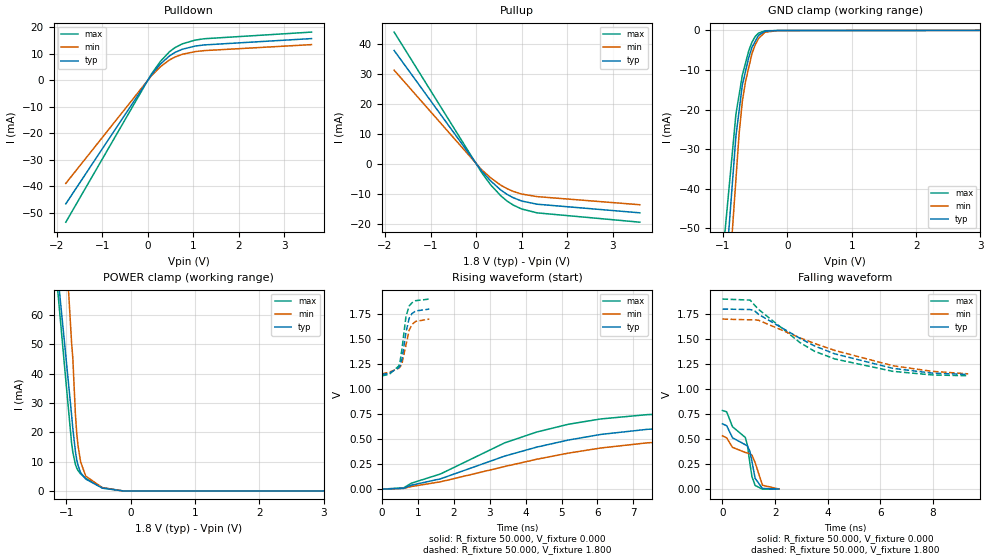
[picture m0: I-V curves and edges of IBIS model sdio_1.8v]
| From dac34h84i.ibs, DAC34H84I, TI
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[Model]   sdio_1.8v
Model_type I/O
Vinl=5.400E-01
Vinh=1.260E+00
Vref=0.000E+00
Rref=1.000E+06
Cref=0.000E+00
Vmeas=9.000E-01
C_comp   6.740E-13   6.530E-13   6.950E-13
[Voltage Range]   1.800E+00   1.700E+00   1.900E+00
[POWER Clamp Reference]   1.800E+00   1.700E+00   1.900E+00
[GND Clamp Reference]   0.000E+00   0.000E+00   0.000E+00
[Pullup Reference]   1.800E+00   1.700E+00   1.900E+00
[Pulldown Reference]   0.000E+00   0.000E+00   0.000E+00
[Temperature Range] 25   125   -40
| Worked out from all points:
|   slope of the pulldown table from 0 to 0.27 V, typ, clamps not added: 45.6 ohm
|   slope of the pullup table from 0 to 0.27 V, typ, clamps not added: 54.8 ohm
|   GND clamp passes 1 mA (typ) near -0.43 V on its own axis
|   POWER clamp passes 1 mA (typ) near -0.45 V on its own axis
|   rising waveform, R_fixture 50.000, V_fixture 0.000: 20-80 % time 3.77ns typ, 4.29ns min, 3.27ns max; typ from 0 V to 0.652 V
|   falling waveform, R_fixture 50.000, V_fixture 0.000: 20-80 % time 870ps typ, 1.05ns min, 732ps max; typ from 0.652 V to 0 V
|   rising waveform, R_fixture 50.000, V_fixture 1.800: 20-80 % time 181ps typ, 197ps min, 170ps max; typ from 1.15 V to 1.8 V
|   falling waveform, R_fixture 50.000, V_fixture 1.800: 20-80 % time 3.42ns typ, 3.84ns min, 2.82ns max; typ from 1.8 V to 1.15 V
[GND Clamp]
-1.8V     -242.4mA   -269.9mA   -195.7mA
-800mV    -26.7mA    -37.63mA   -21.15mA
-750mV    -20.22mA   -26.01mA   -16.21mA
-700mV    -13.73mA   -17.89mA   -11.26mA
-650mV    -10.26mA   -12.81mA   -8.173mA
-600mV    -6.781mA   -9.304mA   -5.08mA
-550mV    -4.257mA   -5.802mA   -2.937mA
-500mV    -2.753mA   -3.618mA   -1.517mA
-450mV    -1.249mA   -2.055mA   -667.8uA
-350mV    -200.6uA   -456.3uA   -72.45uA
-150mV    -15.42uA   -17.32uA   -17.32uA
3.6V      32.18uA    37.62uA    21.08uA
[Power Clamp]
-1.8V     222mA      379.6mA    231.2mA
-1.02V    48.49mA    88.18mA    40.38mA
-920mV    26.11mA    50.82mA    16.48mA
-900mV    21.28mA    45.26mA    13.24mA
-860mV    13.47mA    26.21mA    9.068mA
-840mV    10.76mA    19.8mA     7.859mA
-820mV    8.766mA    15.59mA    6.999mA
-780mV    6.293mA    10.03mA    5.834mA
-700mV    4.052mA    5.069mA    4.276mA
-440mV    932.9uA    1.089mA    1.116mA
-120mV    0A         0A         0A
3.6V      0A         0A         0A
[Pullup]
-1.8V     37.98mA    31.37mA    44.14mA
120mV     -2.343mA   -1.92mA    -2.846mA
320mV     -5.701mA   -4.66mA    -7.03mA
540mV     -8.745mA   -7.128mA   -10.64mA
680mV     -10.23mA   -8.304mA   -12.46mA
820mV     -11.37mA   -9.256mA   -13.84mA
1V        -12.45mA   -10.12mA   -15.12mA
1.34V     -13.53mA   -10.99mA   -16.43mA
3.6V      -16.42mA   -13.71mA   -19.56mA
[Pulldown]
-1.8V     -46.56mA   -38.86mA   -53.48mA
80mV      1.966mA    1.636mA    2.274mA
280mV     6.106mA    5.077mA    7.112mA
480mV     9.176mA    7.651mA    10.74mA
600mV     10.48mA    8.749mA    12.28mA
760mV     11.66mA    9.756mA    13.69mA
1.04V     12.85mA    10.77mA    15.1mA
1.24V     13.29mA    11.15mA    15.62mA
3.6V      15.68mA    13.41mA    18.13mA
[Rising Waveform]
R_fixture = 50.000
V_fixture = 0.000
V_fixture_min = 0.000
V_fixture_max = 0.000
|  time   V(typ)   V(min)   V(max)
0s        303.1uV    373.8uV    325.9uV
610ps     8.633mV    8.615mV    14.26mV
820ps     40.04mV    26.87mV    59.82mV
1.63ns    103.3mV    73.66mV    152mV
3.42ns    331.1mV    226.8mV    463.4mV
4.31ns    420.5mV    299.3mV    571.3mV
5.19ns    491.1mV    360.4mV    648.9mV
6.09ns    547.1mV    411.6mV    702mV
7.39ns    598.5mV    463.5mV    745.3mV
11.14ns   651.9mV    532mV      785.2mV
[Falling Waveform]
R_fixture = 50.000
V_fixture = 0.000
V_fixture_min = 0.000
V_fixture_max = 0.000
|  time   V(typ)   V(min)   V(max)
0s        651.9mV    532mV      785.2mV
160ps     633mV      511.5mV    772.3mV
380ps     512.6mV    417mV      623.1mV
870ps     442.9mV    365.5mV    515.6mV
950ps     429.7mV    360.1mV    434.3mV
1.04ns    378.4mV    353.9mV    262.4mV
1.12ns    275.9mV    339.1mV    124.9mV
1.24ns    107.1mV    265.1mV    36.24mV
1.52ns    5.53mV     38.13mV    -1.427mV
2.14ns    303.1uV    373.8uV    325.9uV
[Rising Waveform]
R_fixture = 50.000
V_fixture = 1.800
V_fixture_min = 1.700
V_fixture_max = 1.900
|  time   V(typ)   V(min)   V(max)
0s        1.146V     1.152V     1.133V
200ps     1.158V     1.169V     1.146V
470ps     1.214V     1.208V     1.231V
510ps     1.237V     1.222V     1.282V
560ps     1.301V     1.257V     1.403V
670ps     1.567V     1.439V     1.725V
760ps     1.709V     1.589V     1.831V
840ps     1.756V     1.647V     1.863V
940ps     1.781V     1.677V     1.884V
1.32ns    1.8V       1.7V       1.9V
[Falling Waveform]
R_fixture = 50.000
V_fixture = 1.800
V_fixture_min = 1.700
V_fixture_max = 1.900
|  time   V(typ)   V(min)   V(max)
0s        1.8V       1.7V       1.9V
1.05ns    1.795V     1.692V     1.89V
1.21ns    1.786V     1.693V     1.842V
1.37ns    1.747V     1.688V     1.797V
2.95ns    1.507V     1.512V     1.464V
3.5ns     1.431V     1.456V     1.378V
4.27ns    1.352V     1.386V     1.301V
6.48ns    1.207V     1.233V     1.177V
7.98ns    1.159V     1.177V     1.141V
9.34ns    1.146V     1.152V     1.133V
[Ramp]
dV/dt_r   3.9031E-01/3.7675E-09   3.1871E-01/4.2841E-09   4.6746E-01/3.2656E-09
dV/dt_f   3.9249E-01/3.4144E-09   3.2885E-01/3.8422E-09   4.5993E-01/2.8128E-09
R_load = 50
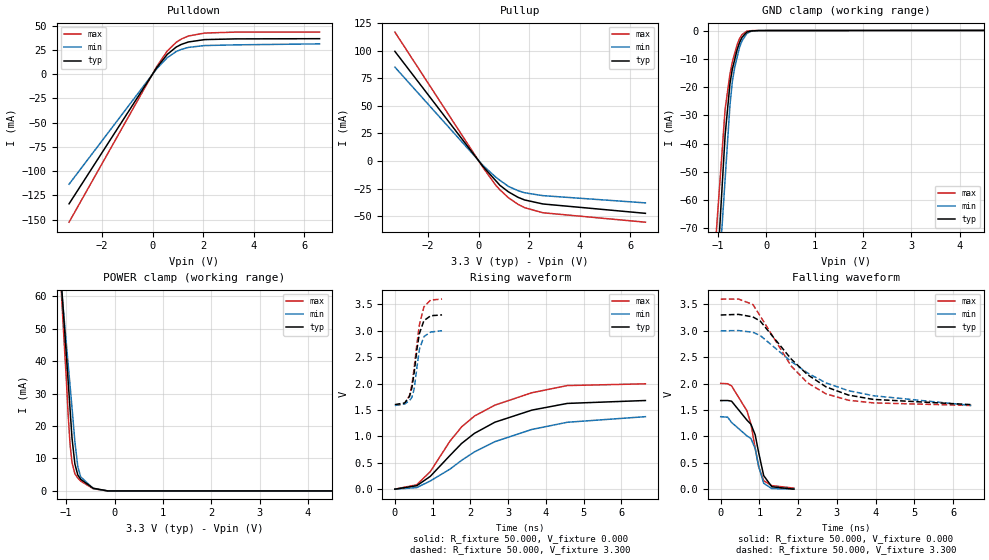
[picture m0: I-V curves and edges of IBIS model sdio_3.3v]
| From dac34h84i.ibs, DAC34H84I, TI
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[Model]   sdio_3.3v
Model_type I/O
Vinl=9.900E-01
Vinh=2.310E+00
Vref=0.000E+00
Rref=1.000E+06
Cref=0.000E+00
Vmeas=1.650E+00
C_comp   6.740E-13   6.530E-13   6.950E-13
[Voltage Range]   3.300E+00   3.000E+00   3.600E+00
[POWER Clamp Reference]   3.300E+00   3.000E+00   3.600E+00
[GND Clamp Reference]   0.000E+00   0.000E+00   0.000E+00
[Pullup Reference]   3.300E+00   3.000E+00   3.600E+00
[Pulldown Reference]   0.000E+00   0.000E+00   0.000E+00
[Temperature Range] 25   125   -40
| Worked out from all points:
|   slope of the pulldown table from 0 to 0.495 V, typ, clamps not added: 27.7 ohm
|   slope of the pullup table from 0 to 0.495 V, typ, clamps not added: 36.4 ohm
|   GND clamp passes 1 mA (typ) near -0.43 V on its own axis
|   POWER clamp passes 1 mA (typ) near -0.47 V on its own axis
|   rising waveform, R_fixture 50.000, V_fixture 0.000: 20-80 % time 1.84ns typ, 2.21ns min, 1.66ns max; typ from 0 V to 1.68 V
|   falling waveform, R_fixture 50.000, V_fixture 0.000: 20-80 % time 459ps typ, 558ps min, 397ps max; typ from 1.68 V to 0 V
|   rising waveform, R_fixture 50.000, V_fixture 3.300: 20-80 % time 198ps typ, 168ps min, 217ps max; typ from 1.6 V to 3.3 V
|   falling waveform, R_fixture 50.000, V_fixture 3.300: 20-80 % time 1.47ns typ, 2ns min, 1.21ns max; typ from 3.3 V to 1.6 V
[GND Clamp]
-3.3V     -756.2mA   -694.8mA   -612.9mA
-850mV    -37.07mA   -52.65mA   -27.84mA
-750mV    -18.8mA    -26.44mA   -15.45mA
-700mV    -13.6mA    -18.06mA   -11.08mA
-650mV    -10.16mA   -12.9mA    -8.012mA
-600mV    -6.706mA   -9.374mA   -4.946mA
-550mV    -4.203mA   -5.845mA   -2.837mA
-500mV    -2.418mA   -3.65mA    -1.45mA
-400mV    -534.9uA   -1.05mA    -226.8uA
-300mV    -145.6uA   -173.5uA   -53.62uA
-150mV    -16.29uA   -18.92uA   -17.23uA
6.6V      55.69uA    64.66uA    46.36uA
[Power Clamp]
-3.32V    541.9mA    436.5mA    646.1mA
-1.02V    46.86mA    49.28mA    40.07mA
-1V       42.55mA    45.91mA    35.32mA
-960mV    33.94mA    39.17mA    23.65mA
-920mV    25.17mA    32.44mA    14.37mA
-880mV    16.35mA    25.71mA    8.766mA
-820mV    8.293mA    15.1mA     5.299mA
-760mV    4.927mA    7.499mA    3.988mA
-700mV    3.57mA     4.341mA    3.042mA
-440mV    829.9uA    746.8uA    668.6uA
-140mV    0A         0A         0A
6.6V      0A         0A         0A
[Pullup]
-3.32V    99.5mA     85.19mA    117mA
180mV     -5.239mA   -4.289mA   -6.259mA
680mV     -18.01mA   -14.77mA   -22.16mA
840mV     -22.1mA    -17.57mA   -26.17mA
1.18V     -28.06mA   -23.11mA   -33.41mA
1.56V     -33mA      -26.92mA   -39.34mA
1.82V     -35.38mA   -28.85mA   -42.36mA
2.54V     -38.99mA   -31.44mA   -46.98mA
6.6V      -47.5mA    -38.02mA   -55.54mA
[Pulldown]
-3.3V     -133.6mA   -113.4mA   -152.5mA
160mV     6.408mA    5.362mA    7.448mA
580mV     20.3mA     16.89mA    23.77mA
940mV     27.94mA    23.31mA    32.83mA
1.14V     30.62mA    25.47mA    36.15mA
1.42V     33.09mA    27.5mA     39.26mA
2.06V     35.53mA    29.4mA     42.26mA
3.3V      36.26mA    30.11mA    43.26mA
6.6V      36.46mA    31.14mA    43.26mA
[Rising Waveform]
R_fixture = 50.000
V_fixture = 0.000
V_fixture_min = 0.000
V_fixture_max = 0.000
|  time   V(typ)   V(min)   V(max)
0s        242uV      316.4uV    235.2uV
580ps     65.89mV    30.15mV    83.54mV
940ps     243.5mV    155.9mV    333.9mV
1.46ns    638.5mV    379.6mV    909.4mV
1.77ns    867.2mV    547.5mV    1.181V
2.11ns    1.058V     706.7mV    1.385V
2.65ns    1.268V     899.9mV    1.591V
3.63ns    1.497V     1.131V     1.826V
4.57ns    1.624V     1.267V     1.962V
6.64ns    1.679V     1.373V     1.995V
[Falling Waveform]
R_fixture = 50.000
V_fixture = 0.000
V_fixture_min = 0.000
V_fixture_max = 0.000
|  time   V(typ)   V(min)   V(max)
0s        1.679V     1.373V     2.004V
180ps     1.68V      1.364V     1.998V
280ps     1.667V     1.264V     1.957V
680ps     1.306V     1.008V     1.482V
780ps     1.231V     959.2mV    1.235V
890ps     1.03V      768.8mV    780.8mV
980ps     693.3mV    433.2mV    424.8mV
1.11ns    256.5mV    112mV      159.8mV
1.32ns    46.03mV    11.95mV    66.98mV
1.89ns    242uV      316.4uV    19.95mV
[Rising Waveform]
R_fixture = 50.000
V_fixture = 3.300
V_fixture_min = 3.000
V_fixture_max = 3.600
|  time   V(typ)   V(min)   V(max)
0s        1.602V     1.586V     1.586V
260ps     1.633V     1.614V     1.614V
390ps     1.76V      1.678V     1.778V
450ps     1.918V     1.738V     1.972V
510ps     2.202V     1.895V     2.292V
590ps     2.677V     2.337V     2.786V
650ps     2.949V     2.65V      3.116V
770ps     3.192V     2.89V      3.455V
950ps     3.284V     2.976V     3.582V
1.25ns    3.3V       3V         3.6V
[Falling Waveform]
R_fixture = 50.000
V_fixture = 3.300
V_fixture_min = 3.000
V_fixture_max = 3.600
|  time   V(typ)   V(min)   V(max)
0s        3.3V       3V         3.6V
460ps     3.312V     3.005V     3.602V
830ps     3.264V     2.973V     3.5V
1.02ns    3.185V     2.912V     3.281V
1.82ns    2.466V     2.42V      2.333V
2.24ns    2.171V     2.202V     2.016V
2.72ns    1.938V     2.013V     1.806V
3.3ns     1.783V     1.866V     1.685V
3.94ns    1.701V     1.771V     1.635V
6.47ns    1.602V     1.586V     1.586V
[Ramp]
dV/dt_r   1.0026E+00/1.8309E-09   8.1805E-01/2.1973E-09   1.1905E+00/1.6599E-09
dV/dt_f   1.0185E+00/1.4756E-09   8.4842E-01/1.9981E-09   1.2082E+00/1.2086E-09
R_load = 50
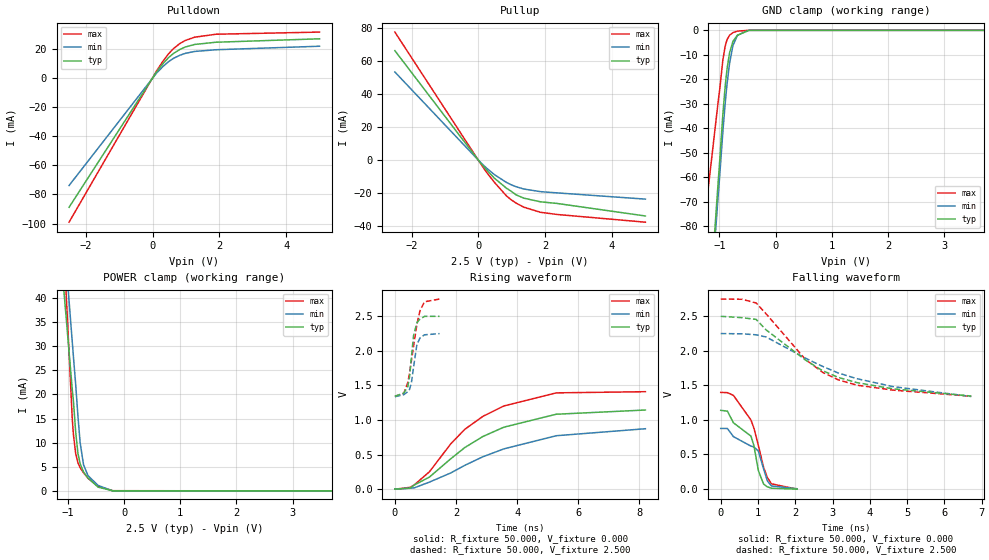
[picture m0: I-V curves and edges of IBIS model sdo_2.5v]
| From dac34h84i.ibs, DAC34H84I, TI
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[Model]   sdo_2.5v
Model_type 3-state
Vref=0.000E+00
Rref=1.000E+06
Cref=0.000E+00
Vmeas=1.250E+00
C_comp   6.000E-13   5.800E-13   6.200E-13
[Voltage Range]   2.500E+00   2.250E+00   2.750E+00
[POWER Clamp Reference]   2.500E+00   2.250E+00   2.750E+00
[GND Clamp Reference]   0.000E+00   0.000E+00   0.000E+00
[Pullup Reference]   2.500E+00   2.250E+00   2.750E+00
[Pulldown Reference]   0.000E+00   0.000E+00   0.000E+00
[Temperature Range] 25   125   -40
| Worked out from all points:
|   slope of the pulldown table from 0 to 0.375 V, typ, clamps not added: 33.1 ohm
|   slope of the pullup table from 0 to 0.375 V, typ, clamps not added: 43.1 ohm
|   GND clamp passes 1 mA (typ) near -0.60 V on its own axis
|   POWER clamp passes 1 mA (typ) near -0.49 V on its own axis
|   rising waveform, R_fixture 50.000, V_fixture 0.000: 20-80 % time 2.38ns typ, 2.91ns min, 2.01ns max; typ from 0 V to 1.15 V
|   falling waveform, R_fixture 50.000, V_fixture 0.000: 20-80 % time 594ps typ, 767ps min, 505ps max; typ from 1.14 V to -0.006 V
|   rising waveform, R_fixture 50.000, V_fixture 2.500: 20-80 % time 167ps typ, 177ps min, 298ps max; typ from 1.34 V to 2.5 V
|   falling waveform, R_fixture 50.000, V_fixture 2.500: 20-80 % time 2.08ns typ, 2.63ns min, 1.64ns max; typ from 2.5 V to 1.34 V
[GND Clamp]
-2.5V     -547.2mA   -529.1mA   -324.3mA
-1.02V    -61.02mA   -66.75mA   -28.59mA
-1V       -54.85mA   -60.76mA   -25.12mA
-940mV    -34.48mA   -41.59mA   -12.29mA
-900mV    -23.4mA    -30.39mA   -6.745mA
-880mV    -18.85mA   -25.43mA   -4.915mA
-860mV    -14.97mA   -20.95mA   -3.593mA
-820mV    -9.198mA   -13.48mA   -1.996mA
-760mV    -4.509mA   -6.183mA   -937.3uA
-680mV    -2.001mA   -2.038mA   -318.5uA
-480mV    0A         0A         0A
5V        0A         0A         0A
[Power Clamp]
-2.5V     237.7mA    267.3mA    394.6mA
-1.02V    34.73mA    45.81mA    38.85mA
-920mV    21.02mA    30.87mA    14.95mA
-900mV    18.7mA     27.91mA    11.74mA
-860mV    12.3mA     22.15mA    7.777mA
-820mV    7.83mA     15.62mA    5.877mA
-780mV    5.628mA    9.994mA    4.811mA
-720mV    3.952mA    5.427mA    3.768mA
-640mV    2.662mA    3.164mA    2.619mA
-460mV    780.6uA    1.128mA    960.8uA
-200mV    34.28uA    5.929uA    45.99uA
5V        0A         0A         0A
[Pullup]
-2.5V     66.28mA    53.37mA    77.51mA
40mV      -1.002mA   -829.1uA   -1.242mA
240mV     -5.741mA   -4.699mA   -7.174mA
480mV     -10.87mA   -8.72mA    -13.36mA
840mV     -16.92mA   -13.41mA   -21.54mA
980mV     -18.73mA   -14.81mA   -23.88mA
1.12V     -20.84mA   -15.96mA   -25.8mA
1.36V     -22.93mA   -17.41mA   -28.39mA
1.86V     -25.15mA   -18.99mA   -31.49mA
2.36V     -26.14mA   -19.75mA   -32.81mA
5V        -33.72mA   -23.52mA   -37.47mA
[Pulldown]
-2.5V     -88.82mA   -73.89mA   -99.05mA
120mV     4.038mA    3.246mA    4.715mA
320mV     9.909mA    7.929mA    11.69mA
480mV     13.85mA    11.06mA    16.47mA
620mV     16.6mA     13.24mA    19.87mA
820mV     19.47mA    15.5mA     23.54mA
980mV     21.13mA    16.76mA    25.61mA
1.26V     22.87mA    18.07mA    27.85mA
1.9V      24.39mA    19.24mA    29.88mA
5V        26.74mA    21.65mA    31.35mA
[Rising Waveform]
R_fixture = 50.000
V_fixture = 0.000
V_fixture_min = 0.000
V_fixture_max = 0.000
|  time   V(typ)   V(min)   V(max)
0s        0V         0V         0V
500ps     15.88mV    12.98mV    26.35mV
640ps     60.61mV    19.81mV    64.65mV
1.13ns    174.8mV    102.1mV    251.2mV
1.83ns    440.1mV    234.8mV    656.1mV
2.29ns    602.4mV    345.1mV    866.4mV
2.88ns    761.8mV    468.8mV    1.053V
3.57ns    897.1mV    583.3mV    1.204V
5.28ns    1.084V     773mV      1.393V
8.2ns     1.145V     874.2mV    1.41V
[Falling Waveform]
R_fixture = 50.000
V_fixture = 0.000
V_fixture_min = 0.000
V_fixture_max = 0.000
|  time   V(typ)   V(min)   V(max)
0s        1.137V     874.2mV    1.397V
180ps     1.125V     873.6mV    1.393V
340ps     956.6mV    755.7mV    1.354V
810ps     764.1mV    618.4mV    997.7mV
890ps     626.9mV    606.4mV    879.8mV
1.01ns    262.4mV    545.1mV    627.3mV
1.15ns    67.7mV     287.8mV    312.8mV
1.25ns    27.66mV    115.3mV    163.5mV
1.36ns    8.091mV    40.34mV    71.83mV
2.05ns    -6.064mV   0V         -5.996mV
[Rising Waveform]
R_fixture = 50.000
V_fixture = 2.500
V_fixture_min = 2.250
V_fixture_max = 2.750
|  time   V(typ)   V(min)   V(max)
0s        1.344V     1.337V     1.341V
290ps     1.39V      1.367V     1.385V
420ps     1.479V     1.409V     1.539V
480ps     1.626V     1.444V     1.675V
540ps     1.91V      1.536V     1.857V
610ps     2.218V     1.762V     2.062V
720ps     2.408V     2.09V      2.383V
820ps     2.46V      2.186V     2.579V
970ps     2.5V       2.233V     2.711V
1.46ns    2.5V       2.25V      2.75V
[Falling Waveform]
R_fixture = 50.000
V_fixture = 2.500
V_fixture_min = 2.250
V_fixture_max = 2.750
|  time   V(typ)   V(min)   V(max)
0s        2.5V       2.25V      2.75V
570ps     2.48V      2.246V     2.747V
950ps     2.455V     2.232V     2.693V
1.22ns    2.302V     2.2V       2.534V
2.27ns    1.867V     1.894V     1.877V
2.72ns    1.715V     1.777V     1.692V
3.15ns    1.615V     1.679V     1.579V
3.65ns    1.539V     1.596V     1.502V
4.62ns    1.449V     1.481V     1.43V
6.72ns    1.344V     1.337V     1.341V
[Ramp]
dV/dt_r   6.8557E-01/2.3819E-09   5.2096E-01/2.9131E-09   8.4167E-01/2.0035E-09
dV/dt_f   6.9364E-01/2.0815E-09   5.4785E-01/2.6234E-09   8.4523E-01/1.6362E-09
R_load = 50
